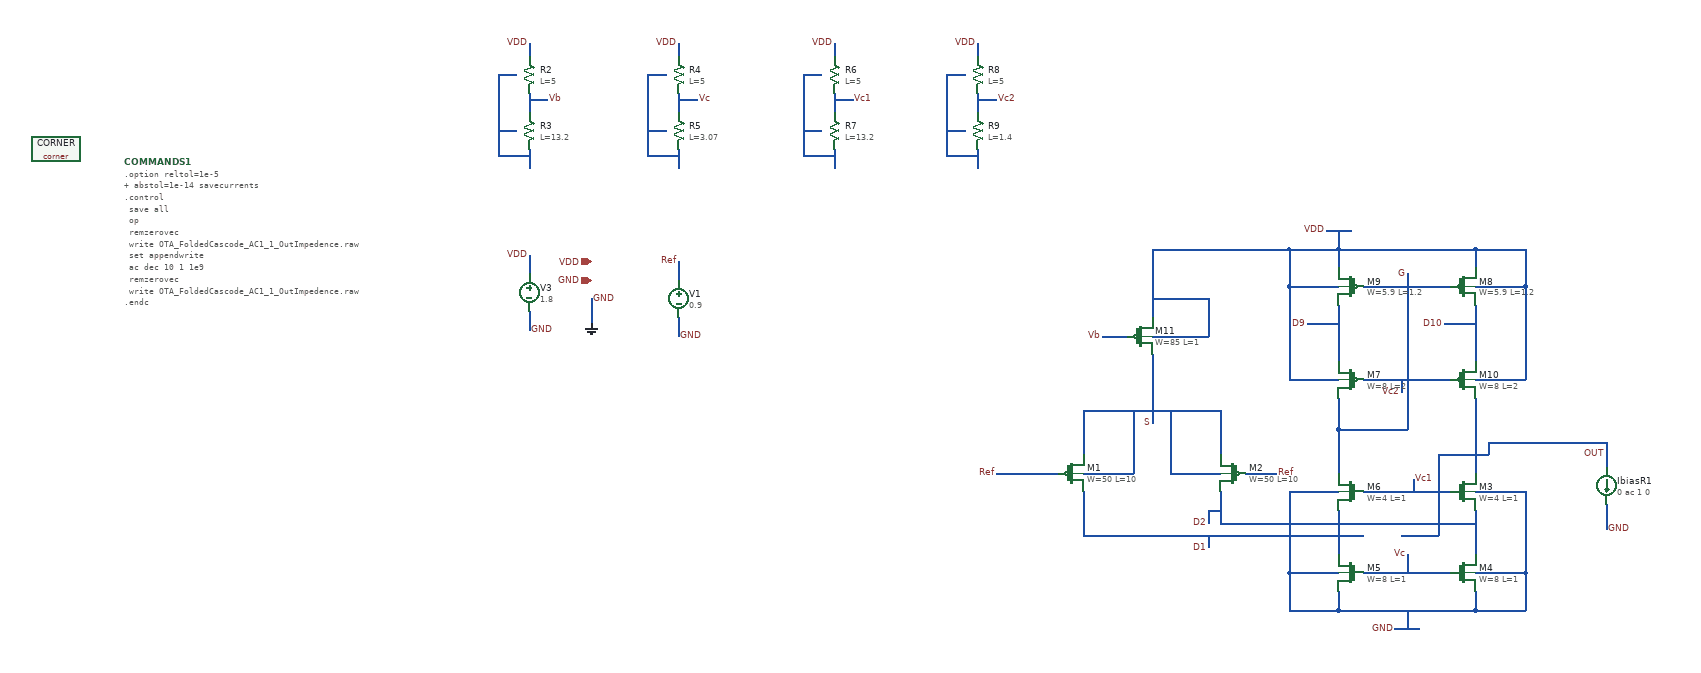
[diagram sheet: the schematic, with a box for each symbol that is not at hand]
v {xschem version=3.4.5 file_version=1.2
}
G {}
K {}
V {}
S {}
E {}
B 2 670 -330 1220 -80 {flags=graph,unlocked


ypos1=0
ypos2=2

subdivy=1
unity=1



subdivx=8
node="\\"out db20()\\""
color=4
dataset=0
unitx=1
logx=1
logy=0

sweep=""
rawfile=$netlist_dir/OTA_FoldedCascode_AC1_1_OutImpedence.raw
sim_type=ac


y2=145




divx=8

y1=35

divy=10
x2=8
x1=0}
B 2 670 -580 1220 -330 {flags=graph,unlocked
rawfile=$netlist_dir/OTA_FoldedCascode_AC1_1_OutImpedence.raw
sim_type=ac
y1=-196.66665
y2=203.33335
ypos1=0
ypos2=2

subdivy=1
unity=1



subdivx=8
node="ph(out) 180-"
color="4 4"
dataset=0
unitx=1
logx=1
logy=0
divx=8
sweep=""

x1=0

x2=8
divy=20}
N 510 -250 510 -230 {
lab=OUT}
N 510 -170 510 -150 {
lab=GND}
N 510 -150 510 -130 {
lab=GND}
N -1120 -500 -1120 -460 {
lab=GND}
N -1220 -480 -1220 -450 {
lab=GND}
N -1220 -570 -1220 -540 {
lab=VDD}
N 510 -270 510 -250 {
lab=OUT}
N 320 -270 420 -270 {
lab=OUT}
N -470 -220 -420 -220 {
lab=Ref}
N -980 -470 -980 -440 {
lab=GND}
N -980 -560 -980 -530 {
lab=Ref}
N 420 -270 510 -270 {
lab=OUT}
N 60 -610 100 -610 {
lab=VDD}
N 170 30 210 30 {
lab=GND}
N 120 -60 260 -60 {
lab=Vc}
N 80 0 300 0 {
lab=GND}
N 300 -30 300 0 {
lab=GND}
N 80 -160 80 -90 {
lab=D1}
N 300 -160 300 -90 {
lab=D2}
N 120 -190 260 -190 {
lab=Vc1}
N -110 -140 300 -140 {
lab=D2}
N -110 -190 -110 -140 {
lab=D2}
N 10 -120 80 -120 {
lab=D1}
N -10 -120 10 -120 {
lab=D1}
N -330 -120 -10 -120 {
lab=D1}
N -330 -190 -330 -120 {
lab=D1}
N -70 -220 -20 -220 {
lab=Ref}
N -420 -220 -370 -220 {
lab=Ref}
N -330 -320 -330 -250 {
lab=S}
N -110 -320 -110 -250 {
lab=S}
N -330 -320 -110 -320 {
lab=S}
N -220 -580 -220 -570 {
lab=VDD}
N -190 -220 -110 -220 {
lab=S}
N -190 -320 -190 -220 {
lab=S}
N -330 -220 -250 -220 {
lab=S}
N -250 -320 -250 -220 {
lab=S}
N 0 -60 80 -60 {
lab=GND}
N 0 -60 0 0 {
lab=GND}
N 0 0 80 0 {
lab=GND}
N 300 -60 380 -60 {
lab=GND}
N 380 -60 380 0 {
lab=GND}
N 300 0 380 0 {
lab=GND}
N 300 -190 380 -190 {
lab=GND}
N 380 -190 380 -140 {
lab=GND}
N 0 -190 80 -190 {
lab=GND}
N 0 -190 0 -150 {
lab=GND}
N 200 -210 200 -190 {
lab=Vc1}
N 190 -90 190 -60 {
lab=Vc}
N -130 -120 -130 -100 {
lab=D1}
N -130 -160 -130 -140 {
lab=D2}
N -130 -160 -110 -160 {
lab=D2}
N -220 -320 -220 -300 {
lab=S}
N 190 0 190 30 {
lab=GND}
N 80 -610 80 -580 {
lab=VDD}
N 0 -150 0 -60 {
lab=GND}
N 380 -140 380 -60 {
lab=GND}
N -220 -570 -220 -560 {
lab=VDD}
N -220 -360 -220 -320 {
lab=S}
N -220 -560 -220 -470 {
lab=VDD}
N -220 -410 -220 -360 {
lab=S}
N -300 -440 -260 -440 {
lab=Vb}
N -220 -410 -220 -400 {
lab=S}
N -220 -440 -130 -440 {
lab=VDD}
N -130 -500 -130 -440 {
lab=VDD}
N -220 -500 -130 -500 {
lab=VDD}
N 80 -30 80 0 {
lab=GND}
N 80 -580 300 -580 {
lab=VDD}
N 300 -580 380 -580 {
lab=VDD}
N 0 -580 80 -580 {
lab=VDD}
N -220 -580 0 -580 {
lab=VDD}
N 80 -290 80 -220 {
lab=G}
N 120 -370 260 -370 {
lab=Vc2}
N 80 -490 80 -400 {
lab=D9}
N 300 -490 300 -400 {
lab=D10}
N 120 -520 260 -520 {
lab=G}
N 80 -290 190 -290 {
lab=G}
N 190 -520 190 -290 {
lab=G}
N 300 -370 370 -370 {
lab=VDD}
N 370 -370 380 -370 {
lab=VDD}
N 380 -420 380 -370 {
lab=VDD}
N 0 -370 80 -370 {
lab=VDD}
N 0 -420 0 -370 {
lab=VDD}
N 0 -520 80 -520 {
lab=VDD}
N 300 -520 380 -520 {
lab=VDD}
N 180 -370 180 -350 {
lab=Vc2}
N 190 -540 190 -520 {
lab=G}
N 250 -460 300 -460 {
lab=D10}
N 30 -460 80 -460 {
lab=D9}
N 300 -340 300 -280 {
lab=OUT}
N 80 -340 80 -290 {
lab=G}
N 300 -570 300 -550 {
lab=VDD}
N 300 -580 300 -570 {
lab=VDD}
N 80 -580 80 -550 {
lab=VDD}
N 0 -580 0 -520 {
lab=VDD}
N 380 -580 380 -520 {
lab=VDD}
N 0 -520 0 -420 {
lab=VDD}
N 380 -520 380 -420 {
lab=VDD}
N 300 -280 300 -220 {
lab=OUT}
N 80 -120 120 -120 {
lab=D1}
N 180 -120 240 -120 {
lab=OUT}
N 240 -250 240 -120 {
lab=OUT}
N 240 -250 300 -250 {
lab=OUT}
N 300 -250 320 -250 {
lab=OUT}
N 320 -270 320 -250 {
lab=OUT}
N -1220 -910 -1220 -890 {
lab=VDD}
N -1220 -740 -1220 -710 {
lab=#net1}
N -1220 -830 -1220 -800 {
lab=Vb}
N -1220 -820 -1190 -820 {
lab=Vb}
N -1250 -860 -1240 -860 {
lab=#net1}
N -1270 -860 -1270 -730 {
lab=#net1}
N -1250 -730 -1220 -730 {
lab=#net1}
N -1250 -770 -1240 -770 {
lab=#net1}
N -1270 -860 -1250 -860 {
lab=#net1}
N -1270 -770 -1250 -770 {
lab=#net1}
N -1270 -730 -1250 -730 {
lab=#net1}
N -980 -910 -980 -890 {
lab=VDD}
N -980 -740 -980 -710 {
lab=#net2}
N -980 -830 -980 -800 {
lab=Vc}
N -980 -820 -950 -820 {
lab=Vc}
N -1010 -860 -1000 -860 {
lab=#net2}
N -1030 -860 -1030 -730 {
lab=#net2}
N -1010 -730 -980 -730 {
lab=#net2}
N -1010 -770 -1000 -770 {
lab=#net2}
N -1030 -860 -1010 -860 {
lab=#net2}
N -1030 -770 -1010 -770 {
lab=#net2}
N -1030 -730 -1010 -730 {
lab=#net2}
N -730 -910 -730 -890 {
lab=VDD}
N -730 -740 -730 -710 {
lab=#net3}
N -730 -830 -730 -800 {
lab=Vc1}
N -730 -820 -700 -820 {
lab=Vc1}
N -760 -860 -750 -860 {
lab=#net3}
N -780 -860 -780 -730 {
lab=#net3}
N -760 -730 -730 -730 {
lab=#net3}
N -760 -770 -750 -770 {
lab=#net3}
N -780 -860 -760 -860 {
lab=#net3}
N -780 -770 -760 -770 {
lab=#net3}
N -780 -730 -760 -730 {
lab=#net3}
N -500 -910 -500 -890 {
lab=VDD}
N -500 -740 -500 -710 {
lab=#net4}
N -500 -830 -500 -800 {
lab=Vc2}
N -500 -820 -470 -820 {
lab=Vc2}
N -530 -860 -520 -860 {
lab=#net4}
N -550 -860 -550 -730 {
lab=#net4}
N -530 -730 -500 -730 {
lab=#net4}
N -530 -770 -520 -770 {
lab=#net4}
N -550 -860 -530 -860 {
lab=#net4}
N -550 -770 -530 -770 {
lab=#net4}
N -550 -730 -530 -730 {
lab=#net4}
C {devices/launcher.sym} 1350 -340 0 0 {name=h1
descr="Annotate OP" 
tclcommand="set show_hidden_texts 1; xschem annotate_op"
}
C {devices/simulator_commands_shown.sym} -1870 -720 0 0 {name=COMMANDS1
simulator=ngspice
only_toplevel=false 
value="
.option reltol=1e-5
+  abstol=1e-14 savecurrents
.control
  save all
  op
  remzerovec 
  write OTA_FoldedCascode_AC1_1_OutImpedence.raw

  set appendwrite
  ac dec 10 1 1e9
  remzerovec
  write OTA_FoldedCascode_AC1_1_OutImpedence.raw
.endc
"}
C {devices/launcher.sym} 1340 -390 0 0 {name=h3
descr="Netlist & sim" 
tclcommand="xschem netlist; xschem simulate"}
C {sky130_fd_pr/corner.sym} -1980 -740 0 0 {name=CORNER only_toplevel=true corner=tt}
C {devices/isource.sym} 510 -200 0 0 {name=IbiasR1 value="0 ac 1 0"}
C {devices/lab_pin.sym} 510 -130 0 1 {name=p3 sig_type=std_logic lab=GND}
C {devices/iopin.sym} -1120 -560 0 0 {name=p4 lab=VDD}
C {devices/iopin.sym} -1120 -530 0 0 {name=p5 lab=GND}
C {devices/vsource.sym} -1220 -510 0 0 {name=V3 value=1.8 savecurrent=false}
C {devices/gnd.sym} -1120 -460 0 0 {name=l4 lab=GND}
C {devices/lab_pin.sym} -1120 -500 0 1 {name=p6 sig_type=std_logic lab=GND}
C {devices/lab_pin.sym} -1220 -450 0 1 {name=p11 sig_type=std_logic lab=GND}
C {devices/lab_pin.sym} -1220 -570 0 0 {name=p12 sig_type=std_logic lab=VDD}
C {devices/vsource.sym} -980 -500 0 0 {name=V1 value=0.9 savecurrent=false}
C {devices/lab_pin.sym} -980 -440 0 1 {name=p7 sig_type=std_logic lab=GND}
C {devices/lab_pin.sym} -980 -560 0 0 {name=p8 sig_type=std_logic lab=Ref}
C {devices/lab_pin.sym} -470 -220 0 0 {name=p9 sig_type=std_logic lab=Ref}
C {devices/lab_wire.sym} 60 -610 0 0 {name=p16 sig_type=std_logic lab=VDD}
C {devices/lab_wire.sym} 170 30 0 0 {name=p17 sig_type=std_logic lab=GND}
C {devices/lab_pin.sym} -130 -100 0 0 {name=p24 sig_type=std_logic lab=D1}
C {devices/lab_pin.sym} -130 -140 0 0 {name=p25 sig_type=std_logic lab=D2

}
C {devices/lab_pin.sym} -220 -300 0 0 {name=p29 sig_type=std_logic lab=S

}
C {devices/lab_pin.sym} 190 -90 0 0 {name=p18 sig_type=std_logic lab=Vc}
C {devices/lab_pin.sym} 200 -210 0 1 {name=p31 sig_type=std_logic lab=Vc1
}
C {sky130_fd_pr/pfet_01v8_lvt.sym} -240 -440 0 0 {name=M11
L=1
W=85
nf=10
mult=5
ad="'int((nf+1)/2) * W/nf * 0.29'" 
pd="'2*int((nf+1)/2) * (W/nf + 0.29)'"
as="'int((nf+2)/2) * W/nf * 0.29'" 
ps="'2*int((nf+2)/2) * (W/nf + 0.29)'"
nrd="'0.29 / W'" nrs="'0.29 / W'"
sa=0 sb=0 sd=0
model=pfet_01v8_lvt
spiceprefix=X
}
C {devices/lab_pin.sym} -300 -440 0 0 {name=p19 sig_type=std_logic lab=Vb}
C {sky130_fd_pr/pfet_01v8_lvt.sym} -350 -220 0 0 {name=M1
L=10
W=50
nf=2
mult=2
ad="'int((nf+1)/2) * W/nf * 0.29'" 
pd="'2*int((nf+1)/2) * (W/nf + 0.29)'"
as="'int((nf+2)/2) * W/nf * 0.29'" 
ps="'2*int((nf+2)/2) * (W/nf + 0.29)'"
nrd="'0.29 / W'" nrs="'0.29 / W'"
sa=0 sb=0 sd=0
model=pfet_01v8_lvt
spiceprefix=X
}
C {sky130_fd_pr/pfet_01v8_lvt.sym} -90 -220 0 1 {name=M2
L=10
W=50
nf=2
mult=2
ad="'int((nf+1)/2) * W/nf * 0.29'" 
pd="'2*int((nf+1)/2) * (W/nf + 0.29)'"
as="'int((nf+2)/2) * W/nf * 0.29'" 
ps="'2*int((nf+2)/2) * (W/nf + 0.29)'"
nrd="'0.29 / W'" nrs="'0.29 / W'"
sa=0 sb=0 sd=0
model=pfet_01v8_lvt
spiceprefix=X
}
C {sky130_fd_pr/nfet_01v8_lvt.sym} 280 -190 0 0 {name=M3
L=1
W=4
nf=1
mult=1
ad="'int((nf+1)/2) * W/nf * 0.29'" 
pd="'2*int((nf+1)/2) * (W/nf + 0.29)'"
as="'int((nf+2)/2) * W/nf * 0.29'" 
ps="'2*int((nf+2)/2) * (W/nf + 0.29)'"
nrd="'0.29 / W'" nrs="'0.29 / W'"
sa=0 sb=0 sd=0
model=nfet_01v8_lvt
spiceprefix=X
}
C {sky130_fd_pr/nfet_01v8_lvt.sym} 280 -60 0 0 {name=M4
L=1
W=8
nf=1
mult=1
ad="'int((nf+1)/2) * W/nf * 0.29'" 
pd="'2*int((nf+1)/2) * (W/nf + 0.29)'"
as="'int((nf+2)/2) * W/nf * 0.29'" 
ps="'2*int((nf+2)/2) * (W/nf + 0.29)'"
nrd="'0.29 / W'" nrs="'0.29 / W'"
sa=0 sb=0 sd=0
model=nfet_01v8_lvt
spiceprefix=X
}
C {sky130_fd_pr/nfet_01v8_lvt.sym} 100 -60 0 1 {name=M5
L=1
W=8
nf=1
mult=1
ad="'int((nf+1)/2) * W/nf * 0.29'" 
pd="'2*int((nf+1)/2) * (W/nf + 0.29)'"
as="'int((nf+2)/2) * W/nf * 0.29'" 
ps="'2*int((nf+2)/2) * (W/nf + 0.29)'"
nrd="'0.29 / W'" nrs="'0.29 / W'"
sa=0 sb=0 sd=0
model=nfet_01v8_lvt
spiceprefix=X
}
C {sky130_fd_pr/nfet_01v8_lvt.sym} 100 -190 0 1 {name=M6
L=1
W=4
nf=1
mult=1
ad="'int((nf+1)/2) * W/nf * 0.29'" 
pd="'2*int((nf+1)/2) * (W/nf + 0.29)'"
as="'int((nf+2)/2) * W/nf * 0.29'" 
ps="'2*int((nf+2)/2) * (W/nf + 0.29)'"
nrd="'0.29 / W'" nrs="'0.29 / W'"
sa=0 sb=0 sd=0
model=nfet_01v8_lvt
spiceprefix=X
}
C {devices/lab_pin.sym} 190 -540 0 0 {name=p20 sig_type=std_logic lab=G

}
C {devices/lab_pin.sym} 250 -460 0 0 {name=p27 sig_type=std_logic lab=D10

}
C {devices/lab_pin.sym} 30 -460 0 0 {name=p28 sig_type=std_logic lab=D9

}
C {devices/lab_pin.sym} 180 -350 0 0 {name=p32 sig_type=std_logic lab=Vc2}
C {sky130_fd_pr/pfet_01v8_lvt.sym} 100 -370 0 1 {name=M7
L=2
W=8
nf=1
mult=1
ad="'int((nf+1)/2) * W/nf * 0.29'" 
pd="'2*int((nf+1)/2) * (W/nf + 0.29)'"
as="'int((nf+2)/2) * W/nf * 0.29'" 
ps="'2*int((nf+2)/2) * (W/nf + 0.29)'"
nrd="'0.29 / W'" nrs="'0.29 / W'"
sa=0 sb=0 sd=0
model=pfet_01v8_lvt
spiceprefix=X
}
C {sky130_fd_pr/pfet_01v8_lvt.sym} 100 -520 0 1 {name=M9
L=1.2
W=5.9
nf=1
mult=1
ad="'int((nf+1)/2) * W/nf * 0.29'" 
pd="'2*int((nf+1)/2) * (W/nf + 0.29)'"
as="'int((nf+2)/2) * W/nf * 0.29'" 
ps="'2*int((nf+2)/2) * (W/nf + 0.29)'"
nrd="'0.29 / W'" nrs="'0.29 / W'"
sa=0 sb=0 sd=0
model=pfet_01v8_lvt
spiceprefix=X
}
C {sky130_fd_pr/pfet_01v8_lvt.sym} 280 -520 0 0 {name=M8
L=1.2
W=5.9
nf=1
mult=1
ad="'int((nf+1)/2) * W/nf * 0.29'" 
pd="'2*int((nf+1)/2) * (W/nf + 0.29)'"
as="'int((nf+2)/2) * W/nf * 0.29'" 
ps="'2*int((nf+2)/2) * (W/nf + 0.29)'"
nrd="'0.29 / W'" nrs="'0.29 / W'"
sa=0 sb=0 sd=0
model=pfet_01v8_lvt
spiceprefix=X
}
C {sky130_fd_pr/pfet_01v8_lvt.sym} 280 -370 0 0 {name=M10
L=2
W=8
nf=1
mult=1
ad="'int((nf+1)/2) * W/nf * 0.29'" 
pd="'2*int((nf+1)/2) * (W/nf + 0.29)'"
as="'int((nf+2)/2) * W/nf * 0.29'" 
ps="'2*int((nf+2)/2) * (W/nf + 0.29)'"
nrd="'0.29 / W'" nrs="'0.29 / W'"
sa=0 sb=0 sd=0
model=pfet_01v8_lvt
spiceprefix=X
}
C {devices/lab_pin.sym} -20 -220 0 1 {name=p10 sig_type=std_logic lab=Ref}
C {devices/lab_pin.sym} 510 -250 0 0 {name=p14 sig_type=std_logic lab=OUT}
C {devices/lab_wire.sym} -1220 -910 0 0 {name=p39 sig_type=std_logic lab=VDD}
C {sky130_fd_pr/res_xhigh_po_0p35.sym} -1220 -860 0 0 {name=R2
L=5
model=res_xhigh_po_0p35
spiceprefix=X
mult=1}
C {sky130_fd_pr/res_xhigh_po_0p35.sym} -1220 -770 0 0 {name=R3
L=13.2
model=res_xhigh_po_0p35
spiceprefix=X
mult=1}
C {devices/lab_wire.sym} -980 -910 0 0 {name=p26 sig_type=std_logic lab=VDD}
C {sky130_fd_pr/res_xhigh_po_0p35.sym} -980 -860 0 0 {name=R4
L=5
model=res_xhigh_po_0p35
spiceprefix=X
mult=1}
C {sky130_fd_pr/res_xhigh_po_0p35.sym} -980 -770 0 0 {name=R5
L=3.07
model=res_xhigh_po_0p35
spiceprefix=X
mult=1}
C {devices/lab_wire.sym} -730 -910 0 0 {name=p40 sig_type=std_logic lab=VDD}
C {sky130_fd_pr/res_xhigh_po_0p35.sym} -730 -860 0 0 {name=R6
L=5
model=res_xhigh_po_0p35
spiceprefix=X
mult=1}
C {sky130_fd_pr/res_xhigh_po_0p35.sym} -730 -770 0 0 {name=R7
L=13.2
model=res_xhigh_po_0p35
spiceprefix=X
mult=1}
C {devices/lab_wire.sym} -500 -910 0 0 {name=p43 sig_type=std_logic lab=VDD}
C {sky130_fd_pr/res_xhigh_po_0p35.sym} -500 -860 0 0 {name=R8
L=5
model=res_xhigh_po_0p35
spiceprefix=X
mult=1}
C {sky130_fd_pr/res_xhigh_po_0p35.sym} -500 -770 0 0 {name=R9
L=1.4
model=res_xhigh_po_0p35
spiceprefix=X
mult=1}
C {devices/lab_pin.sym} -1190 -820 0 1 {name=p34 sig_type=std_logic lab=Vb}
C {devices/lab_pin.sym} -950 -820 0 1 {name=p36 sig_type=std_logic lab=Vc}
C {devices/lab_pin.sym} -700 -820 0 1 {name=p41 sig_type=std_logic lab=Vc1}
C {devices/lab_pin.sym} -470 -820 0 1 {name=p44 sig_type=std_logic lab=Vc2}
